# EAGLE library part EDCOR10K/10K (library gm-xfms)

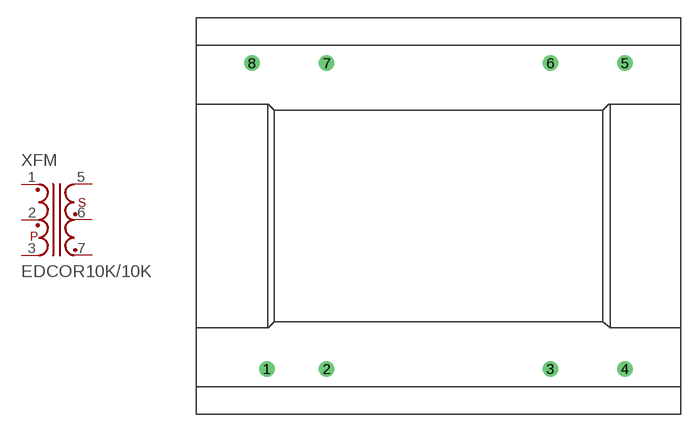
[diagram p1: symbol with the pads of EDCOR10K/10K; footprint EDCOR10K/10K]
Designator prefix XFM

## EDCOR10K/10K  [EDCOR10K/10K]
1  1  pas
2  2  pas
3  3  pas
5  6  pas
6  5  pas
7  4  pas

## Footprint EDCOR10K/10K (pad centres in mm)
drill 0.7 pad 1.3 round: 1 -14.605,-13.018; 2 -9.525,-13.018; 3 9.525,-13.018; 4 15.875,-13.018; 5 15.875,13.018; 6 9.525,13.018; 7 -9.525,13.018; 8 -15.875,13.018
